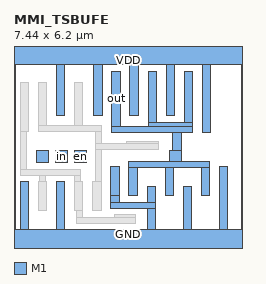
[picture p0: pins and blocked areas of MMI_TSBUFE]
MACRO MMI_TSBUFE
	CLASS CORE ;
	FOREIGN MMI_TSBUFE 0 0 ;
	SIZE 7.44 BY 6.2 ;
	SYMMETRY X Y ;
	SITE CORE1 ;
	PIN out
		DIRECTION output ;
		USE SIGNAL ;
		PORT
			LAYER M1 ;
			RECT 3.195 3.775 3.475 5.57 ;
			LAYER M1 ;
			RECT 4.375 3.895 4.655 5.57 ;
			LAYER M1 ;
			RECT 5.555 3.895 5.835 5.57 ;
			LAYER M1 ;
			RECT 4.375 3.775 5.835 3.895 ;
			LAYER M1 ;
			RECT 3.195 3.585 5.835 3.775 ;
			LAYER M1 ;
			RECT 5.17 2.98 5.455 3.585 ;
			LAYER M1 ;
			RECT 5.08 2.625 5.46 2.98 ;
			LAYER M1 ;
			RECT 3.75 2.435 6.39 2.625 ;
			LAYER M1 ;
			RECT 3.75 1.525 4.03 2.435 ;
			LAYER M1 ;
			RECT 4.93 1.525 5.21 2.435 ;
			LAYER M1 ;
			RECT 6.11 1.525 6.39 2.435 ;
		END
		AntennaDiffArea 4.0656 ;
	END out
	PIN GND
		DIRECTION inout ;
		USE GROUND ;
		PORT
			LAYER M1 ;
			RECT 0.2 0.42 0.48 1.985 ;
			LAYER M1 ;
			RECT 1.38 0.42 1.66 1.985 ;
			LAYER M1 ;
			RECT 3.16 1.525 3.44 2.48 ;
			LAYER M1 ;
			RECT 3.15 1.3 3.435 1.525 ;
			LAYER M1 ;
			RECT 4.34 1.3 4.62 1.805 ;
			LAYER M1 ;
			RECT 3.15 1.105 4.62 1.3 ;
			LAYER M1 ;
			RECT 4.34 0.42 4.62 1.105 ;
			LAYER M1 ;
			RECT 5.52 0.42 5.8 1.805 ;
			LAYER M1 ;
			RECT 6.7 0.42 6.98 2.48 ;
			LAYER M1 ;
			RECT 0 -0.42 7.44 0.42 ;
		END
	END GND
	PIN enb
		DIRECTION input ;
		USE SIGNAL ;
		PORT
			LAYER M1 ;
			RECT 0.74 2.6 1.12 2.98 ;
		END
		AntennaGateArea 0.40725 ;
	END enb
	PIN VDD
		DIRECTION inout ;
		USE POWER ;
		PORT
			LAYER M1 ;
			RECT 0 5.78 7.44 6.62 ;
			LAYER M1 ;
			RECT 1.38 4.14 1.66 5.78 ;
			LAYER M1 ;
			RECT 2.605 4.115 2.885 5.78 ;
			LAYER M1 ;
			RECT 3.785 4.115 4.065 5.78 ;
			LAYER M1 ;
			RECT 4.965 4.115 5.245 5.78 ;
			LAYER M1 ;
			RECT 6.145 3.585 6.425 5.78 ;
		END
	END VDD
	PIN en
		DIRECTION input ;
		USE SIGNAL ;
		PORT
			LAYER M1 ;
			RECT 1.98 2.6 2.36 2.98 ;
		END
		AntennaGateArea 0.40725 ;
	END en
	PIN in
		DIRECTION input ;
		USE SIGNAL ;
		PORT
			LAYER M1 ;
			RECT 1.36 2.6 1.74 2.98 ;
		END
		AntennaGateArea 0.8145 ;
	END in
	OBS
		LAYER M1 ;
		RECT 0.2 3.6 0.48 5.205 ;
		LAYER M1 ;
		RECT 0.79 3.79 1.07 5.205 ;
		LAYER M1 ;
		RECT 1.97 3.79 2.25 5.205 ;
		LAYER M1 ;
		RECT 0.79 3.6 2.84 3.79 ;
		LAYER M1 ;
		RECT 0.2 2.375 0.395 3.6 ;
		LAYER M1 ;
		RECT 2.645 3.205 2.84 3.6 ;
		LAYER M1 ;
		RECT 3.655 3.205 4.715 3.295 ;
		LAYER M1 ;
		RECT 2.645 3.015 4.715 3.205 ;
		LAYER M1 ;
		RECT 0.2 2.185 2.16 2.375 ;
		LAYER M1 ;
		RECT 0.83 1.985 1.025 2.185 ;
		LAYER M1 ;
		RECT 1.97 1.985 2.16 2.185 ;
		LAYER M1 ;
		RECT 2.645 1.985 2.84 3.015 ;
		LAYER M1 ;
		RECT 0.79 1.015 1.07 1.985 ;
		LAYER M1 ;
		RECT 1.97 1.015 2.25 1.985 ;
		LAYER M1 ;
		RECT 2.56 1.015 2.84 1.985 ;
		LAYER M1 ;
		RECT 2.055 0.815 2.25 1.015 ;
		LAYER M1 ;
		RECT 3.295 0.815 3.965 0.9 ;
		LAYER M1 ;
		RECT 2.055 0.62 3.97 0.815 ;
	END
END MMI_TSBUFE
